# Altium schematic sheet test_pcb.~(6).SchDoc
size A4; SheetNumber: 1; SheetTotal: 1

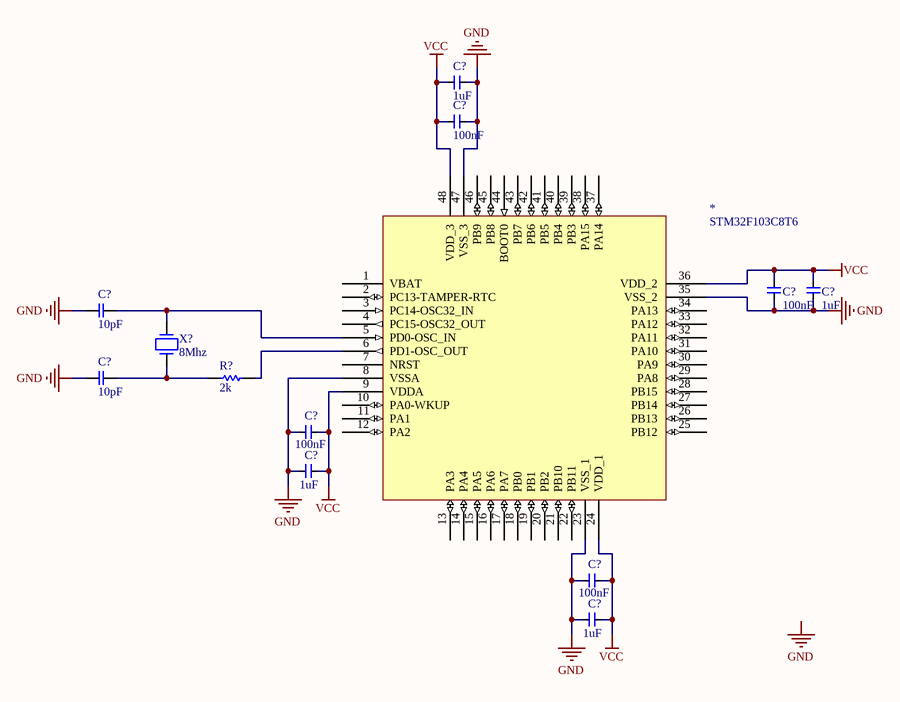
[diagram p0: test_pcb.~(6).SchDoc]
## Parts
(Parts that share a designator on the sheet are numbered #1, #2 ... from top to bottom, then left to right.)
*  STM32F103C8T6
C?#1  1uF
C?#2  100nF
C?#3  100nF
C?#4  1uF
C?#5  10pF
C?#6  10pF
C?#7  100nF
C?#8  1uF
C?#9  100nF
C?#10  1uF
R?  2k
X?  8Mhz

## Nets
GND: *.8(VSSA) *.23(VSS_1) *.35(VSS_2) *.47(VSS_3) C?#1.1 C?#2.1 C?#3.1 C?#4.1 C?#5.1 C?#6.1 C?#7.1 C?#8.1 C?#9.1 C?#10.1
VCC: *.9(VDDA) *.24(VDD_1) *.36(VDD_2) *.48(VDD_3) C?#1.2 C?#2.2 C?#3.2 C?#4.2 C?#7.2 C?#8.2 C?#9.2 C?#10.2
Net*_5: *.5(PD0-OSC_IN) C?#5.2 X?.2
Net*_6: *.6(PD1-OSC_OUT) R?.2
NetC?#6_2: C?#6.2 R?.4 X?.1

Not connected (* = marked no-connect by the designer): * 1(VBAT) 2(PC13-TAMPER-RTC) 3(PC14-OSC32_IN) 4(PC15-OSC32_OUT) 7(NRST) 10(PA0-WKUP) 11(PA1) 12(PA2) 13(PA3) 14(PA4) 15(PA5) 16(PA6) 17(PA7) 18(PB0) 19(PB1) 20(PB2) 21(PB10) 22(PB11) 25(PB12) 26(PB13) 27(PB14) 28(PB15) 29(PA8) 30(PA9) 31(PA10) 32(PA11) 33(PA12) 34(PA13) 37(PA14) 38(PA15) 39(PB3) 40(PB4) 41(PB5) 42(PB6) 43(PB7) 44(BOOT0) 45(PB8) 46(PB9)

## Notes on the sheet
- Labels drawn without touching a wire or pin: GND

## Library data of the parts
* = STM32F103C8T6: ARM Cortex-M3 STM32 F1 Microcontroller 32-Bit 72MHz 64kB FLASH LQFP48 STM32F103C8T6; Manufacturer: STMicroelectronics; Package Body Material: Plastic; Clock Frequency: 16MHz; Number of I/O Lines: 37; Package Equivalence Code: QFP48,.35SQ,20; Power Supplies: 2.5/3.3; Max Supply Current: 50mA; Max Supply Voltage: 3.6V; Min Supply Voltage: 2V; Nominal Supply Voltage: 3.3V; Time @ Peak Reflow Temperature-Max (s): 30s; Peripherals: POR; Interface: I2C; Qualification Status: Not Qualified
C?#1 C?#4 C?#8 C?#10 = GRM033R60J105MEA2D: Ceramic Capacitor, Multilayer, Ceramic, 6.3V, 20% +Tol, 20% -Tol, X5R, 15% TC, 1uF, Surface Mount, 0201; Manufacturer: Murata; Multilayer: Yes
C?#2 C?#3 C?#7 C?#9 = GRM033C80J104KE15D: Ceramic Capacitor, Multilayer, Ceramic, 6.3V, 10% +Tol, 10% -Tol, X6S, 22% TC, 0.1uF, Surface Mount, 0201; Manufacturer: Murata; Multilayer: Yes
C?#5 C?#6 = 06036A100FAT2A: Ceramic Capacitor, Ceramic, 6.3V, 1% +Tol, 1% -Tol, C0G, -/+30ppm/Cel TC, 0.00001uF, Surface Mount, 0603; Manufacturer: Kyocera AVX; Multilayer: No
R? = RT0402BRD072KL: Fixed Resistor, Thin Film, 0.0625W, 2000ohm, 50V, 0.1% +/-Tol, 25ppm/Cel, Surface Mount, 0402; Manufacturer: Yageo; Additional Feature: HIGH PRECISION; Power: 62.5mW; Rated Temperature: 70°C; Temperature Coefficient (ppm/Cel): 25; Package Height: 0.3mm; Package Length: 1mm; Package Width: 0.5mm
X? = ASDDV-8.000MHZ-LC-T3: Osc, 8MHZ, Cmos/hcmos/lvcmos, SMD Rohs Compliant: Yes; Manufacturer: Abracon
